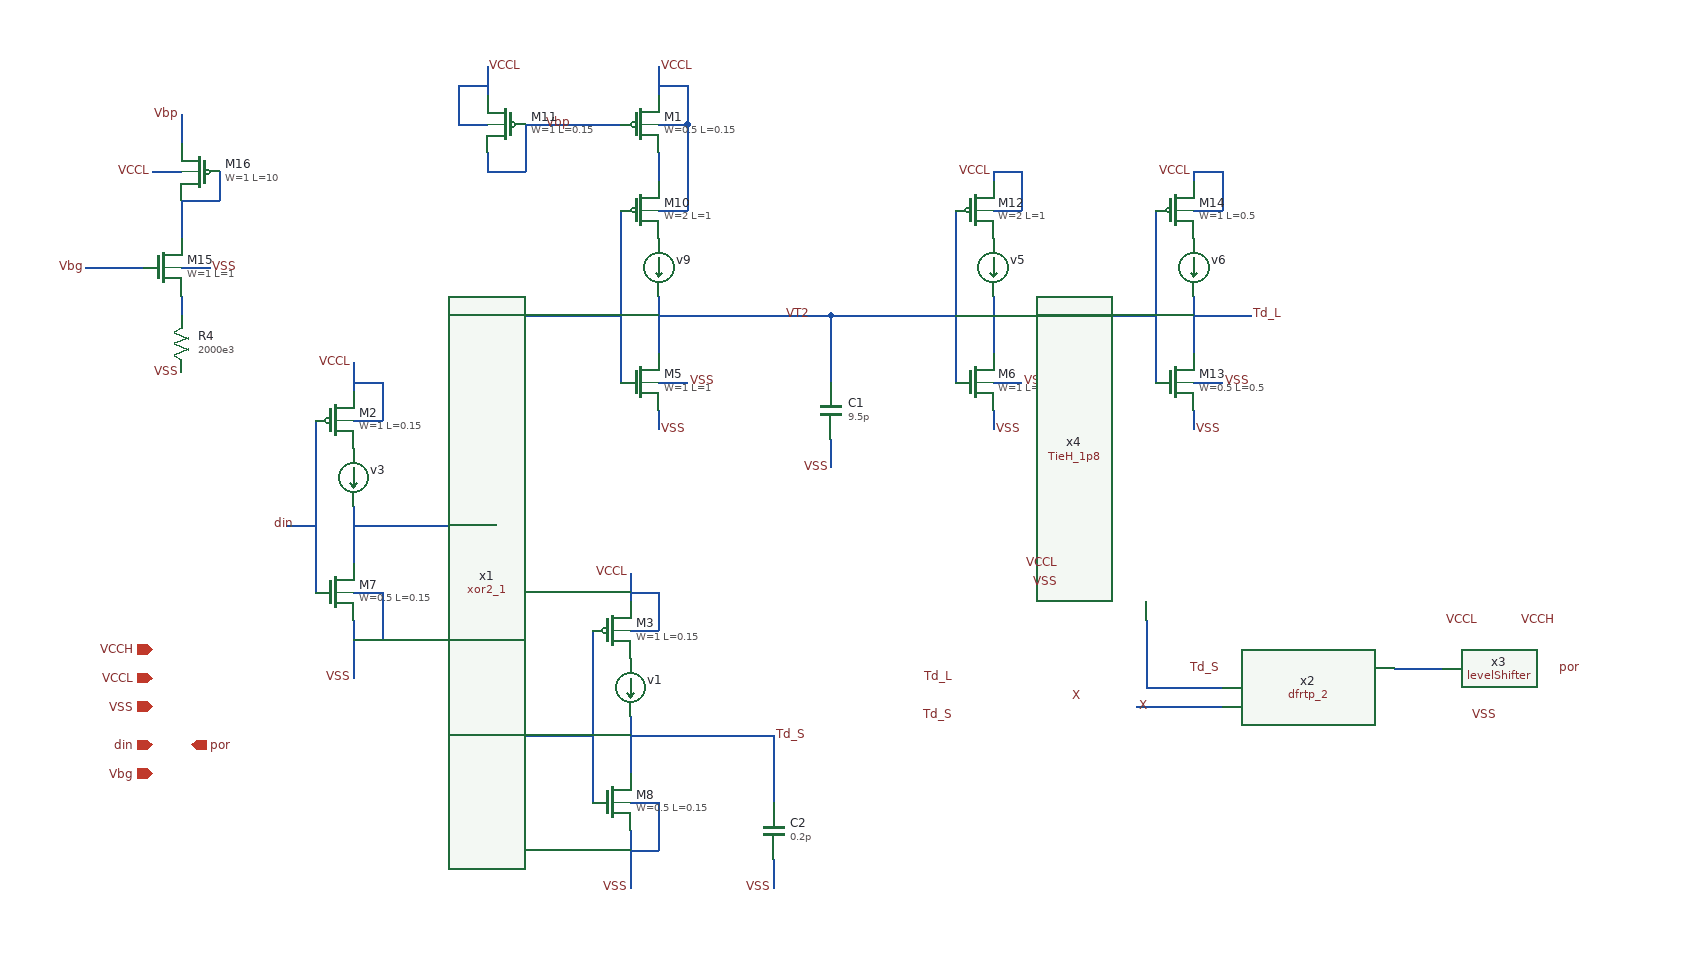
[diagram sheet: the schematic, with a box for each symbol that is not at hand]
v {xschem version=3.4.5 file_version=1.2
}
G {}
K {}
V {}
S {}
E {}
N 650 -630 680 -630 {lab=VSS}
N 650 -680 650 -660 {
lab=VT2}
N 650 -810 680 -810 {lab=VCCL}
N 650 -870 650 -840 {lab=#net1}
N 650 -720 650 -680 {
lab=VT2}
N 610 -810 610 -630 {
lab=#net2}
N 650 -700 710 -700 {
lab=VT2}
N 680 -850 680 -810 {
lab=VCCL}
N 580 -700 610 -700 {
lab=#net2}
N 620 -190 650 -190 {lab=VSS}
N 620 -160 620 -100 {
lab=VSS}
N 620 -240 620 -220 {
lab=Td_S}
N 620 -370 650 -370 {lab=VCCL}
N 620 -430 620 -400 {lab=VCCL}
N 620 -280 620 -240 {
lab=Td_S}
N 580 -370 580 -190 {
lab=#net2}
N 620 -260 680 -260 {
lab=Td_S}
N 650 -410 650 -370 {
lab=VCCL}
N 620 -410 650 -410 {
lab=VCCL}
N 650 -190 650 -140 {
lab=VSS}
N 620 -140 650 -140 {
lab=VSS}
N 550 -260 580 -260 {
lab=#net2}
N 650 -900 680 -900 {lab=VCCL}
N 650 -960 650 -930 {lab=VCCL}
N 680 -940 680 -900 {
lab=VCCL}
N 680 -900 680 -850 {
lab=VCCL}
N 650 -940 680 -940 {
lab=VCCL}
N 480 -700 480 -260 {
lab=#net2}
N 830 -700 830 -630 { lab=VT2}
N 830 -570 830 -540 { lab=VSS}
N 1200 -310 1240 -310 {
lab=#net3}
N 1150 -290 1240 -290 {
lab=X}
N 1420 -330 1470 -330 {
lab=#net4}
N 330 -410 360 -410 {lab=VSS}
N 330 -380 330 -320 {
lab=VSS}
N 330 -460 330 -440 {
lab=#net2}
N 330 -590 360 -590 {lab=VCCL}
N 330 -650 330 -620 {lab=VCCL}
N 330 -500 330 -460 {
lab=#net2}
N 290 -590 290 -410 {
lab=din}
N 330 -480 390 -480 {
lab=#net2}
N 360 -630 360 -590 {
lab=VCCL}
N 330 -630 360 -630 {
lab=VCCL}
N 360 -410 360 -360 {
lab=VSS}
N 330 -360 360 -360 {
lab=VSS}
N 260 -480 290 -480 {
lab=din}
N 390 -480 480 -480 {
lab=#net2}
N 770 -260 770 -190 { lab=Td_S}
N 770 -130 770 -100 { lab=VSS}
N 480 -700 580 -700 {
lab=#net2}
N 780 -700 830 -700 {
lab=VT2}
N 710 -700 780 -700 {
lab=VT2}
N 650 -600 650 -580 {
lab=VSS}
N 590 -900 610 -900 {
lab=Vbp}
N 480 -260 550 -260 {
lab=#net2}
N 690 -260 770 -260 {
lab=Td_S}
N 680 -260 690 -260 {
lab=Td_S}
N 440 -900 470 -900 {lab=VCCL}
N 470 -960 470 -930 {lab=VCCL}
N 440 -940 440 -900 {
lab=VCCL}
N 440 -940 470 -940 {
lab=VCCL}
N 510 -900 510 -850 {
lab=Vbp}
N 470 -850 510 -850 {
lab=Vbp}
N 510 -900 590 -900 {
lab=Vbp}
N 1000 -630 1030 -630 {lab=VSS}
N 1000 -680 1000 -660 {
lab=#net5}
N 1000 -810 1030 -810 {lab=VCCL}
N 1000 -720 1000 -680 {
lab=#net5}
N 960 -810 960 -630 {
lab=VT2}
N 1030 -850 1030 -810 {
lab=VCCL}
N 930 -700 960 -700 {
lab=VT2}
N 830 -700 930 -700 {
lab=VT2}
N 1000 -600 1000 -580 {
lab=VSS}
N 1000 -850 1000 -840 {
lab=VCCL}
N 1000 -850 1030 -850 {
lab=VCCL}
N 1210 -630 1240 -630 {lab=VSS}
N 1210 -680 1210 -660 {
lab=Td_L}
N 1210 -810 1240 -810 {lab=VCCL}
N 1210 -720 1210 -680 {
lab=Td_L}
N 1170 -810 1170 -630 {
lab=#net5}
N 1210 -700 1270 -700 {
lab=Td_L}
N 1240 -850 1240 -810 {
lab=VCCL}
N 1210 -600 1210 -580 {
lab=VSS}
N 1210 -850 1210 -840 {
lab=VCCL}
N 1210 -850 1240 -850 {
lab=VCCL}
N 1000 -700 1040 -700 {
lab=#net5}
N 1080 -700 1080 -630 { lab=#net5}
N 1080 -570 1080 -540 { lab=VSS}
N 1040 -700 1080 -700 {
lab=#net5}
N 1080 -700 1170 -700 {
lab=#net5}
N 1160 -380 1160 -310 {
lab=#net3}
N 1160 -310 1200 -310 {
lab=#net3}
N 150 -750 180 -750 {lab=VSS}
N 150 -810 150 -780 {
lab=#net6}
N 120 -850 150 -850 {lab=VCCL}
N 150 -910 150 -880 {lab=Vbp}
N 150 -820 190 -820 {
lab=#net6}
N 190 -850 190 -820 {
lab=#net6}
N 150 -820 150 -810 {
lab=#net6}
N 100 -750 110 -750 {
lab=VCCL}
N 50 -750 100 -750 {
lab=VCCL}
N 150 -720 150 -700 {
lab=#net7}
N 470 -870 470 -850 {
lab=Vbp}
C {devices/ammeter.sym} 650 -750 0 0 {name=v9}
C {devices/ammeter.sym} 620 -310 0 0 {name=v1}
C {devices/lab_pin.sym} 620 -430 0 0 {name=p4 sig_type=std_logic lab=VCCL}
C {devices/lab_pin.sym} 620 -100 0 0 {name=p5 sig_type=std_logic lab=VSS}
C {devices/lab_pin.sym} 650 -960 0 1 {name=p7 sig_type=std_logic lab=VCCL}
C {devices/capa.sym} 830 -600 0 0 {name=C1
m=50
value=9.5p
footprint=1206
device="ceramic capacitor"}
C {devices/lab_pin.sym} 830 -540 0 0 {name=p1 sig_type=std_logic lab=VSS}
C {sky130_stdcells/dfrtp_2.sym} 1330 -310 0 0 {name=x2 VGND=VSS VNB=VSS VPB=VCCL VPWR=VCCL prefix=sky130_fd_sc_hd__ }
C {devices/lab_pin.sym} 1270 -700 2 0 {name=p2 sig_type=std_logic lab=Td_L}
C {devices/lab_pin.sym} 770 -260 2 0 {name=p9 sig_type=std_logic lab=Td_S}
C {devices/lab_pin.sym} 1590 -330 2 0 {name=p11 sig_type=std_logic lab=por}
C {devices/title.sym} 160 -30 0 0 {name=l2 author="Stephen Wu"}
C {devices/ipin.sym} 120 -320 0 0 {name=p6 lab=VCCL}
C {devices/ipin.sym} 120 -290 0 0 {name=p12 lab=VSS}
C {devices/ipin.sym} 120 -250 0 0 {name=p14 lab=din}
C {devices/ipin.sym} 120 -220 0 0 {name=p15 lab=Vbg}
C {devices/opin.sym} 160 -250 0 0 {name=p16 lab=por}
C {devices/ammeter.sym} 330 -530 0 0 {name=v3}
C {devices/lab_pin.sym} 330 -650 0 0 {name=p17 sig_type=std_logic lab=VCCL}
C {devices/lab_pin.sym} 330 -320 0 0 {name=p18 sig_type=std_logic lab=VSS}
C {devices/lab_pin.sym} 270 -480 0 0 {name=p3 sig_type=std_logic lab=din}
C {devices/capa.sym} 770 -160 0 0 {name=C2
m=20
value=0.2p
footprint=1206
device="ceramic capacitor"}
C {devices/lab_pin.sym} 770 -100 0 0 {name=p20 sig_type=std_logic lab=VSS}
C {sky130_stdcells/xor2_1.sym} 1020 -300 0 0 {name=x1 VGND=VSS VNB=VSS VPB=VCCL VPWR=VCCL prefix=sky130_fd_sc_hd__ }
C {devices/lab_pin.sym} 960 -320 0 0 {name=p22 sig_type=std_logic lab=Td_L}
C {devices/lab_pin.sym} 960 -280 0 0 {name=p23 sig_type=std_logic lab=Td_S}
C {devices/lab_wire.sym} 1080 -300 0 1 {name=p24 lab=X}
C {levelShifter.sym} 1530 -330 0 0 {name=x3}
C {devices/lab_wire.sym} 1510 -380 0 0 {name=p25 lab=VCCL}
C {devices/lab_wire.sym} 1530 -280 0 0 {name=p26 lab=VSS}
C {devices/lab_wire.sym} 1150 -290 0 1 {name=p27 lab=X}
C {devices/lab_pin.sym} 1240 -330 0 0 {name=p28 sig_type=std_logic lab=Td_S}
C {devices/lab_pin.sym} 680 -630 2 0 {name=p13 sig_type=std_logic lab=VSS}
C {devices/lab_pin.sym} 560 -900 3 1 {name=p30 sig_type=std_logic lab=Vbp}
C {sky130_fd_pr/pfet_01v8.sym} 630 -900 0 0 {name=M1
L=0.15
W=0.5
nf=1
mult=1
ad="'int((nf+1)/2) * W/nf * 0.29'" 
pd="'2*int((nf+1)/2) * (W/nf + 0.29)'"
as="'int((nf+2)/2) * W/nf * 0.29'" 
ps="'2*int((nf+2)/2) * (W/nf + 0.29)'"
nrd="'0.29 / W'" nrs="'0.29 / W'"
sa=0 sb=0 sd=0
model=pfet_01v8
spiceprefix=X
}
C {sky130_fd_pr/pfet_01v8.sym} 310 -590 0 0 {name=M2
L=0.15
W=1
nf=1
mult=2
ad="'int((nf+1)/2) * W/nf * 0.29'" 
pd="'2*int((nf+1)/2) * (W/nf + 0.29)'"
as="'int((nf+2)/2) * W/nf * 0.29'" 
ps="'2*int((nf+2)/2) * (W/nf + 0.29)'"
nrd="'0.29 / W'" nrs="'0.29 / W'"
sa=0 sb=0 sd=0
model=pfet_01v8
spiceprefix=X
}
C {sky130_fd_pr/pfet_01v8.sym} 600 -370 0 0 {name=M3
L=0.15
W=1
nf=1
mult=2
ad="'int((nf+1)/2) * W/nf * 0.29'" 
pd="'2*int((nf+1)/2) * (W/nf + 0.29)'"
as="'int((nf+2)/2) * W/nf * 0.29'" 
ps="'2*int((nf+2)/2) * (W/nf + 0.29)'"
nrd="'0.29 / W'" nrs="'0.29 / W'"
sa=0 sb=0 sd=0
model=pfet_01v8
spiceprefix=X
}
C {sky130_fd_pr/nfet_01v8.sym} 630 -630 0 0 {name=M5
L=1
W=1
nf=2 
mult=1
ad="'int((nf+1)/2) * W/nf * 0.29'" 
pd="'2*int((nf+1)/2) * (W/nf + 0.29)'"
as="'int((nf+2)/2) * W/nf * 0.29'" 
ps="'2*int((nf+2)/2) * (W/nf + 0.29)'"
nrd="'0.29 / W'" nrs="'0.29 / W'"
sa=0 sb=0 sd=0
model=nfet_01v8
spiceprefix=X
}
C {sky130_fd_pr/nfet_01v8.sym} 310 -410 0 0 {name=M7
L=0.15
W=0.5
nf=1 
mult=2
ad="'int((nf+1)/2) * W/nf * 0.29'" 
pd="'2*int((nf+1)/2) * (W/nf + 0.29)'"
as="'int((nf+2)/2) * W/nf * 0.29'" 
ps="'2*int((nf+2)/2) * (W/nf + 0.29)'"
nrd="'0.29 / W'" nrs="'0.29 / W'"
sa=0 sb=0 sd=0
model=nfet_01v8
spiceprefix=X
}
C {sky130_fd_pr/nfet_01v8.sym} 600 -190 0 0 {name=M8
L=0.15
W=0.5
nf=1 
mult=2
ad="'int((nf+1)/2) * W/nf * 0.29'" 
pd="'2*int((nf+1)/2) * (W/nf + 0.29)'"
as="'int((nf+2)/2) * W/nf * 0.29'" 
ps="'2*int((nf+2)/2) * (W/nf + 0.29)'"
nrd="'0.29 / W'" nrs="'0.29 / W'"
sa=0 sb=0 sd=0
model=nfet_01v8
spiceprefix=X
}
C {sky130_fd_pr/pfet_01v8.sym} 630 -810 0 0 {name=M10
L=1
W=2
nf=2
mult=1
ad="'int((nf+1)/2) * W/nf * 0.29'" 
pd="'2*int((nf+1)/2) * (W/nf + 0.29)'"
as="'int((nf+2)/2) * W/nf * 0.29'" 
ps="'2*int((nf+2)/2) * (W/nf + 0.29)'"
nrd="'0.29 / W'" nrs="'0.29 / W'"
sa=0 sb=0 sd=0
model=pfet_01v8
spiceprefix=X
}
C {devices/lab_pin.sym} 470 -960 0 1 {name=p32 sig_type=std_logic lab=VCCL}
C {sky130_fd_pr/pfet_01v8.sym} 490 -900 0 1 {name=M11
L=0.15
W=1
nf=1
mult=16
ad="'int((nf+1)/2) * W/nf * 0.29'" 
pd="'2*int((nf+1)/2) * (W/nf + 0.29)'"
as="'int((nf+2)/2) * W/nf * 0.29'" 
ps="'2*int((nf+2)/2) * (W/nf + 0.29)'"
nrd="'0.29 / W'" nrs="'0.29 / W'"
sa=0 sb=0 sd=0
model=pfet_01v8
spiceprefix=X
}
C {devices/lab_pin.sym} 650 -580 2 0 {name=p29 sig_type=std_logic lab=VSS}
C {devices/ammeter.sym} 1000 -750 0 0 {name=v5}
C {devices/lab_pin.sym} 1030 -630 2 0 {name=p31 sig_type=std_logic lab=VSS}
C {sky130_fd_pr/nfet_01v8.sym} 980 -630 0 0 {name=M6
L=1
W=1
nf=2 
mult=1
ad="'int((nf+1)/2) * W/nf * 0.29'" 
pd="'2*int((nf+1)/2) * (W/nf + 0.29)'"
as="'int((nf+2)/2) * W/nf * 0.29'" 
ps="'2*int((nf+2)/2) * (W/nf + 0.29)'"
nrd="'0.29 / W'" nrs="'0.29 / W'"
sa=0 sb=0 sd=0
model=nfet_01v8
spiceprefix=X
}
C {sky130_fd_pr/pfet_01v8.sym} 980 -810 0 0 {name=M12
L=1
W=2
nf=2
mult=1
ad="'int((nf+1)/2) * W/nf * 0.29'" 
pd="'2*int((nf+1)/2) * (W/nf + 0.29)'"
as="'int((nf+2)/2) * W/nf * 0.29'" 
ps="'2*int((nf+2)/2) * (W/nf + 0.29)'"
nrd="'0.29 / W'" nrs="'0.29 / W'"
sa=0 sb=0 sd=0
model=pfet_01v8
spiceprefix=X
}
C {devices/lab_pin.sym} 1000 -580 2 0 {name=p36 sig_type=std_logic lab=VSS}
C {devices/lab_pin.sym} 1000 -850 3 1 {name=p37 sig_type=std_logic lab=VCCL}
C {devices/ammeter.sym} 1210 -750 0 0 {name=v6}
C {devices/lab_pin.sym} 1240 -630 2 0 {name=p21 sig_type=std_logic lab=VSS}
C {sky130_fd_pr/nfet_01v8.sym} 1190 -630 0 0 {name=M13
L=0.5
W=0.5
nf=1 
mult=1
ad="'int((nf+1)/2) * W/nf * 0.29'" 
pd="'2*int((nf+1)/2) * (W/nf + 0.29)'"
as="'int((nf+2)/2) * W/nf * 0.29'" 
ps="'2*int((nf+2)/2) * (W/nf + 0.29)'"
nrd="'0.29 / W'" nrs="'0.29 / W'"
sa=0 sb=0 sd=0
model=nfet_01v8
spiceprefix=X
}
C {sky130_fd_pr/pfet_01v8.sym} 1190 -810 0 0 {name=M14
L=0.5
W=1
nf=1
mult=1
ad="'int((nf+1)/2) * W/nf * 0.29'" 
pd="'2*int((nf+1)/2) * (W/nf + 0.29)'"
as="'int((nf+2)/2) * W/nf * 0.29'" 
ps="'2*int((nf+2)/2) * (W/nf + 0.29)'"
nrd="'0.29 / W'" nrs="'0.29 / W'"
sa=0 sb=0 sd=0
model=pfet_01v8
spiceprefix=X
}
C {devices/lab_pin.sym} 1210 -580 2 0 {name=p38 sig_type=std_logic lab=VSS}
C {devices/lab_pin.sym} 1210 -850 3 1 {name=p39 sig_type=std_logic lab=VCCL}
C {devices/capa.sym} 1080 -600 0 0 {name=C3
m=50
value=9.5p
footprint=1206
device="ceramic capacitor"}
C {devices/lab_pin.sym} 1080 -540 0 0 {name=p41 sig_type=std_logic lab=VSS}
C {devices/lab_pin.sym} 780 -700 2 0 {name=p42 sig_type=std_logic lab=VT2}
C {devices/ipin.sym} 120 -350 0 0 {name=p40 lab=VCCH}
C {devices/lab_wire.sym} 1550 -380 0 1 {name=p43 lab=VCCH}
C {TieH_1p8.sym} 1130 -410 0 0 {name=x4}
C {devices/lab_wire.sym} 1070 -440 0 0 {name=p44 lab=VCCL}
C {devices/lab_pin.sym} 1070 -420 0 0 {name=p45 sig_type=std_logic lab=VSS}
C {devices/ngspice_probe.sym} 150 -790 0 0 {name=r3}
C {devices/lab_pin.sym} 180 -750 2 0 {name=p46 sig_type=std_logic lab=VSS}
C {sky130_fd_pr/nfet_g5v0d10v5.sym} 130 -750 0 0 {name=M15
L=1
W=1
nf=1
mult=1
ad="'int((nf+1)/2) * W/nf * 0.29'" 
pd="'2*int((nf+1)/2) * (W/nf + 0.29)'"
as="'int((nf+2)/2) * W/nf * 0.29'" 
ps="'2*int((nf+2)/2) * (W/nf + 0.29)'"
nrd="'0.29 / W'" nrs="'0.29 / W'"
sa=0 sb=0 sd=0
model=nfet_g5v0d10v5
spiceprefix=X
}
C {sky130_fd_pr/pfet_01v8.sym} 170 -850 0 1 {name=M16
L=10
W=1
nf=1
mult=1
ad="'int((nf+1)/2) * W/nf * 0.29'" 
pd="'2*int((nf+1)/2) * (W/nf + 0.29)'"
as="'int((nf+2)/2) * W/nf * 0.29'" 
ps="'2*int((nf+2)/2) * (W/nf + 0.29)'"
nrd="'0.29 / W'" nrs="'0.29 / W'"
sa=0 sb=0 sd=0
model=pfet_01v8
spiceprefix=X
}
C {devices/lab_pin.sym} 150 -640 0 0 {name=p47 sig_type=std_logic lab=VSS}
C {devices/res.sym} 150 -670 0 1 {name=R4
value=2000e3
footprint=1206
device=resistor
m=1}
C {devices/ngspice_probe.sym} 150 -710 0 0 {name=r5}
C {devices/lab_pin.sym} 120 -850 0 0 {name=p8 sig_type=std_logic lab=VCCL}
C {devices/lab_pin.sym} 150 -910 3 1 {name=p10 sig_type=std_logic lab=Vbp}
C {devices/lab_pin.sym} 50 -750 0 0 {name=p19 sig_type=std_logic lab=Vbg}
